VERSION 5.8 ;
BUSBITCHARS "[]" ;
DIVIDERCHAR "/" ;

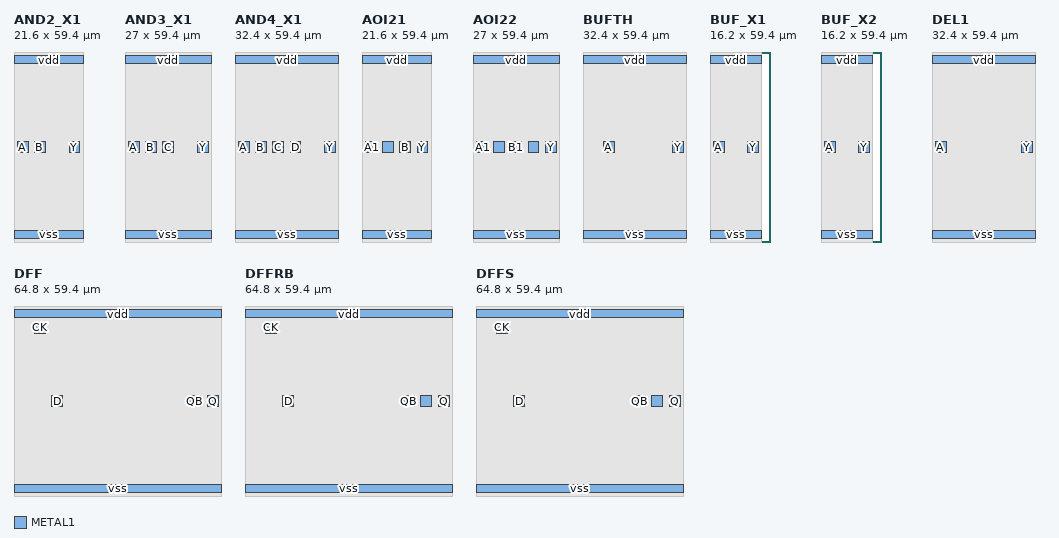
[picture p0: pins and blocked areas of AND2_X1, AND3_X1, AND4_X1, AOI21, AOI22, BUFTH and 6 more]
MACRO AND2_X1
  CLASS CORE ;
  FOREIGN AND2_X1 0.000 0.000 ;
  ORIGIN 0.000 0.000 ;
  SIZE 21.600 BY 59.400 ;
  SYMMETRY X Y ;
  SITE TR1UM ;
  PIN A
    DIRECTION INPUT ;
    USE SIGNAL ;
    PORT
      LAYER METAL1 ;
        RECT 1.000 28.000 4.400 31.400 ;
    END
  END A
  PIN B
    DIRECTION INPUT ;
    USE SIGNAL ;
    PORT
      LAYER METAL1 ;
        RECT 6.400 28.000 9.800 31.400 ;
    END
  END B
  PIN Y
    DIRECTION OUTPUT ;
    USE SIGNAL ;
    PORT
      LAYER METAL1 ;
        RECT 17.200 28.000 20.600 31.400 ;
    END
  END Y
  PIN vdd
    DIRECTION INOUT ;
    USE POWER ;
    SHAPE ABUTMENT ;
    PORT
      LAYER METAL1 ;
        RECT 0.000 55.700 21.600 58.300 ;
    END
  END vdd
  PIN vss
    DIRECTION INOUT ;
    USE GROUND ;
    SHAPE ABUTMENT ;
    PORT
      LAYER METAL1 ;
        RECT 0.000 1.100 21.600 3.700 ;
    END
  END vss
  OBS
    LAYER METAL1 ;
      RECT 0.000 0.000 21.600 59.400 ;
    LAYER VIA1 ;
      RECT 0.000 0.000 21.600 59.400 ;
  END
END AND2_X1

MACRO AND3_X1
  CLASS CORE ;
  FOREIGN AND3_X1 0.000 0.000 ;
  ORIGIN 0.000 0.000 ;
  SIZE 27.000 BY 59.400 ;
  SYMMETRY X Y ;
  SITE TR1UM ;
  PIN A
    DIRECTION INPUT ;
    USE SIGNAL ;
    PORT
      LAYER METAL1 ;
        RECT 1.000 28.000 4.400 31.400 ;
    END
  END A
  PIN B
    DIRECTION INPUT ;
    USE SIGNAL ;
    PORT
      LAYER METAL1 ;
        RECT 6.400 28.000 9.800 31.400 ;
    END
  END B
  PIN C
    DIRECTION INPUT ;
    USE SIGNAL ;
    PORT
      LAYER METAL1 ;
        RECT 11.800 28.000 15.200 31.400 ;
    END
  END C
  PIN Y
    DIRECTION OUTPUT ;
    USE SIGNAL ;
    PORT
      LAYER METAL1 ;
        RECT 22.600 28.000 26.000 31.400 ;
    END
  END Y
  PIN vdd
    DIRECTION INOUT ;
    USE POWER ;
    SHAPE ABUTMENT ;
    PORT
      LAYER METAL1 ;
        RECT 0.000 55.700 27.000 58.300 ;
    END
  END vdd
  PIN vss
    DIRECTION INOUT ;
    USE GROUND ;
    SHAPE ABUTMENT ;
    PORT
      LAYER METAL1 ;
        RECT 0.000 1.100 27.000 3.700 ;
    END
  END vss
  OBS
    LAYER METAL1 ;
      RECT 0.000 0.000 27.000 59.400 ;
    LAYER VIA1 ;
      RECT 0.000 0.000 27.000 59.400 ;
  END
END AND3_X1

MACRO AND4_X1
  CLASS CORE ;
  FOREIGN AND4_X1 0.000 0.000 ;
  ORIGIN 0.000 0.000 ;
  SIZE 32.400 BY 59.400 ;
  SYMMETRY X Y ;
  SITE TR1UM ;
  PIN A
    DIRECTION INPUT ;
    USE SIGNAL ;
    PORT
      LAYER METAL1 ;
        RECT 1.000 28.000 4.400 31.400 ;
    END
  END A
  PIN B
    DIRECTION INPUT ;
    USE SIGNAL ;
    PORT
      LAYER METAL1 ;
        RECT 6.400 28.000 9.800 31.400 ;
    END
  END B
  PIN C
    DIRECTION INPUT ;
    USE SIGNAL ;
    PORT
      LAYER METAL1 ;
        RECT 11.800 28.000 15.200 31.400 ;
    END
  END C
  PIN D
    DIRECTION INPUT ;
    USE SIGNAL ;
    PORT
      LAYER METAL1 ;
        RECT 17.200 28.000 20.600 31.400 ;
    END
  END D
  PIN Y
    DIRECTION OUTPUT ;
    USE SIGNAL ;
    PORT
      LAYER METAL1 ;
        RECT 28.000 28.000 31.400 31.400 ;
    END
  END Y
  PIN vdd
    DIRECTION INOUT ;
    USE POWER ;
    SHAPE ABUTMENT ;
    PORT
      LAYER METAL1 ;
        RECT 0.000 55.700 32.400 58.300 ;
    END
  END vdd
  PIN vss
    DIRECTION INOUT ;
    USE GROUND ;
    SHAPE ABUTMENT ;
    PORT
      LAYER METAL1 ;
        RECT 0.000 1.100 32.400 3.700 ;
    END
  END vss
  OBS
    LAYER METAL1 ;
      RECT 0.000 0.000 32.400 59.400 ;
    LAYER VIA1 ;
      RECT 0.000 0.000 32.400 59.400 ;
  END
END AND4_X1

MACRO AOI21
  CLASS CORE ;
  FOREIGN AOI21 0.000 0.000 ;
  ORIGIN 0.000 0.000 ;
  SIZE 21.600 BY 59.400 ;
  SYMMETRY X Y ;
  SITE TR1UM ;
  PIN A1
    DIRECTION INPUT ;
    USE SIGNAL ;
    PORT
      LAYER METAL1 ;
        RECT 1.000 28.000 4.400 31.400 ;
    END
  END A1
  PIN A2
    DIRECTION INPUT ;
    USE SIGNAL ;
    PORT
      LAYER METAL1 ;
        RECT 6.400 28.000 9.800 31.400 ;
    END
  END A2
  PIN B
    DIRECTION INPUT ;
    USE SIGNAL ;
    PORT
      LAYER METAL1 ;
        RECT 11.800 28.000 15.200 31.400 ;
    END
  END B
  PIN Y
    DIRECTION OUTPUT ;
    USE SIGNAL ;
    PORT
      LAYER METAL1 ;
        RECT 17.200 28.000 20.600 31.400 ;
    END
  END Y
  PIN vdd
    DIRECTION INOUT ;
    USE POWER ;
    SHAPE ABUTMENT ;
    PORT
      LAYER METAL1 ;
        RECT 0.000 55.700 21.600 58.300 ;
    END
  END vdd
  PIN vss
    DIRECTION INOUT ;
    USE GROUND ;
    SHAPE ABUTMENT ;
    PORT
      LAYER METAL1 ;
        RECT 0.000 1.100 21.600 3.700 ;
    END
  END vss
  OBS
    LAYER METAL1 ;
      RECT 0.000 0.000 21.600 59.400 ;
    LAYER VIA1 ;
      RECT 0.000 0.000 21.600 59.400 ;
  END
END AOI21

MACRO AOI22
  CLASS CORE ;
  FOREIGN AOI22 0.000 0.000 ;
  ORIGIN 0.000 0.000 ;
  SIZE 27.000 BY 59.400 ;
  SYMMETRY X Y ;
  SITE TR1UM ;
  PIN A1
    DIRECTION INPUT ;
    USE SIGNAL ;
    PORT
      LAYER METAL1 ;
        RECT 1.000 28.000 4.400 31.400 ;
    END
  END A1
  PIN A2
    DIRECTION INPUT ;
    USE SIGNAL ;
    PORT
      LAYER METAL1 ;
        RECT 6.400 28.000 9.800 31.400 ;
    END
  END A2
  PIN B1
    DIRECTION INPUT ;
    USE SIGNAL ;
    PORT
      LAYER METAL1 ;
        RECT 11.800 28.000 15.200 31.400 ;
    END
  END B1
  PIN B2
    DIRECTION INPUT ;
    USE SIGNAL ;
    PORT
      LAYER METAL1 ;
        RECT 17.200 28.000 20.600 31.400 ;
    END
  END B2
  PIN Y
    DIRECTION OUTPUT ;
    USE SIGNAL ;
    PORT
      LAYER METAL1 ;
        RECT 22.600 28.000 26.000 31.400 ;
    END
  END Y
  PIN vdd
    DIRECTION INOUT ;
    USE POWER ;
    SHAPE ABUTMENT ;
    PORT
      LAYER METAL1 ;
        RECT 0.000 55.700 27.000 58.300 ;
    END
  END vdd
  PIN vss
    DIRECTION INOUT ;
    USE GROUND ;
    SHAPE ABUTMENT ;
    PORT
      LAYER METAL1 ;
        RECT 0.000 1.100 27.000 3.700 ;
    END
  END vss
  OBS
    LAYER METAL1 ;
      RECT 0.000 0.000 27.000 59.400 ;
    LAYER VIA1 ;
      RECT 0.000 0.000 27.000 59.400 ;
  END
END AOI22

MACRO BUFTH
  CLASS CORE ;
  FOREIGN BUFTH 0.000 0.000 ;
  ORIGIN 0.000 0.000 ;
  SIZE 32.400 BY 59.400 ;
  SYMMETRY X Y ;
  SITE TR1UM ;
  PIN A
    DIRECTION INPUT ;
    USE SIGNAL ;
    PORT
      LAYER METAL1 ;
        RECT 6.400 28.000 9.800 31.400 ;
    END
  END A
  PIN Y
    DIRECTION OUTPUT ;
    USE SIGNAL ;
    PORT
      LAYER METAL1 ;
        RECT 28.000 28.000 31.400 31.400 ;
    END
  END Y
  PIN vdd
    DIRECTION INOUT ;
    USE POWER ;
    SHAPE ABUTMENT ;
    PORT
      LAYER METAL1 ;
        RECT 0.000 55.700 32.400 58.300 ;
    END
  END vdd
  PIN vss
    DIRECTION INOUT ;
    USE GROUND ;
    SHAPE ABUTMENT ;
    PORT
      LAYER METAL1 ;
        RECT 0.000 1.100 32.400 3.700 ;
    END
  END vss
  OBS
    LAYER METAL1 ;
      RECT 0.000 0.000 32.400 59.400 ;
    LAYER VIA1 ;
      RECT 0.000 0.000 32.400 59.400 ;
  END
END BUFTH

MACRO BUF_X1
  CLASS CORE ;
  FOREIGN BUF_X1 0.000 0.000 ;
  ORIGIN 0.000 0.000 ;
  SIZE 16.200 BY 59.400 ;
  SYMMETRY X Y ;
  SITE TR1UM ;
  PIN A
    DIRECTION INPUT ;
    USE SIGNAL ;
    PORT
      LAYER METAL1 ;
        RECT 1.000 28.000 4.400 31.400 ;
    END
  END A
  PIN Y
    DIRECTION OUTPUT ;
    USE SIGNAL ;
    PORT
      LAYER METAL1 ;
        RECT 11.800 28.000 15.200 31.400 ;
    END
  END Y
  PIN vdd
    DIRECTION INOUT ;
    USE POWER ;
    SHAPE ABUTMENT ;
    PORT
      LAYER METAL1 ;
        RECT 0.000 55.700 16.200 58.300 ;
    END
  END vdd
  PIN vss
    DIRECTION INOUT ;
    USE GROUND ;
    SHAPE ABUTMENT ;
    PORT
      LAYER METAL1 ;
        RECT 0.000 1.100 16.200 3.700 ;
    END
  END vss
  OBS
    LAYER METAL1 ;
      RECT 0.000 0.000 16.200 59.400 ;
    LAYER VIA1 ;
      RECT 0.000 0.000 16.200 59.400 ;
  END
END BUF_X1

MACRO BUF_X2
  CLASS CORE ;
  FOREIGN BUF_X2 0.000 0.000 ;
  ORIGIN 0.000 0.000 ;
  SIZE 16.200 BY 59.400 ;
  SYMMETRY X Y ;
  SITE TR1UM ;
  PIN A
    DIRECTION INPUT ;
    USE SIGNAL ;
    PORT
      LAYER METAL1 ;
        RECT 1.000 28.000 4.400 31.400 ;
    END
  END A
  PIN Y
    DIRECTION OUTPUT ;
    USE SIGNAL ;
    PORT
      LAYER METAL1 ;
        RECT 11.800 28.000 15.200 31.400 ;
    END
  END Y
  PIN vdd
    DIRECTION INOUT ;
    USE POWER ;
    SHAPE ABUTMENT ;
    PORT
      LAYER METAL1 ;
        RECT 0.000 55.700 16.200 58.300 ;
    END
  END vdd
  PIN vss
    DIRECTION INOUT ;
    USE GROUND ;
    SHAPE ABUTMENT ;
    PORT
      LAYER METAL1 ;
        RECT 0.000 1.100 16.200 3.700 ;
    END
  END vss
  OBS
    LAYER METAL1 ;
      RECT 0.000 0.000 16.200 59.400 ;
    LAYER VIA1 ;
      RECT 0.000 0.000 16.200 59.400 ;
  END
END BUF_X2

MACRO DEL1
  CLASS CORE ;
  FOREIGN DEL1 0.000 0.000 ;
  ORIGIN 0.000 0.000 ;
  SIZE 32.400 BY 59.400 ;
  SYMMETRY X Y ;
  SITE TR1UM ;
  PIN A
    DIRECTION INPUT ;
    USE SIGNAL ;
    PORT
      LAYER METAL1 ;
        RECT 1.000 28.000 4.400 31.400 ;
    END
  END A
  PIN Y
    DIRECTION OUTPUT ;
    USE SIGNAL ;
    PORT
      LAYER METAL1 ;
        RECT 28.000 28.000 31.400 31.400 ;
    END
  END Y
  PIN vdd
    DIRECTION INOUT ;
    USE POWER ;
    SHAPE ABUTMENT ;
    PORT
      LAYER METAL1 ;
        RECT 0.000 55.700 32.400 58.300 ;
    END
  END vdd
  PIN vss
    DIRECTION INOUT ;
    USE GROUND ;
    SHAPE ABUTMENT ;
    PORT
      LAYER METAL1 ;
        RECT 0.000 1.100 32.400 3.700 ;
    END
  END vss
  OBS
    LAYER METAL1 ;
      RECT 0.000 0.000 32.400 59.400 ;
    LAYER VIA1 ;
      RECT 0.000 0.000 32.400 59.400 ;
  END
END DEL1

MACRO DFF
  CLASS CORE ;
  FOREIGN DFF 0.000 0.000 ;
  ORIGIN 0.000 0.000 ;
  SIZE 64.800 BY 59.400 ;
  SYMMETRY X Y ;
  SITE TR1UM ;
  PIN CK
    DIRECTION INPUT ;
    USE SIGNAL ;
    PORT
      LAYER METAL1 ;
        RECT 6.400 50.900 9.800 54.300 ;
    END
  END CK
  PIN D
    DIRECTION INPUT ;
    USE SIGNAL ;
    PORT
      LAYER METAL1 ;
        RECT 11.800 27.900 15.200 31.300 ;
    END
  END D
  PIN Q
    DIRECTION OUTPUT ;
    USE SIGNAL ;
    PORT
      LAYER METAL1 ;
        RECT 60.400 27.900 63.800 31.300 ;
    END
  END Q
  PIN QB
    DIRECTION OUTPUT ;
    USE SIGNAL ;
    PORT
      LAYER METAL1 ;
        RECT 55.000 27.900 58.400 31.300 ;
    END
  END QB
  PIN vdd
    DIRECTION INOUT ;
    USE POWER ;
    SHAPE ABUTMENT ;
    PORT
      LAYER METAL1 ;
        RECT 0.000 55.700 64.800 58.300 ;
    END
  END vdd
  PIN vss
    DIRECTION INOUT ;
    USE GROUND ;
    SHAPE ABUTMENT ;
    PORT
      LAYER METAL1 ;
        RECT 0.000 1.100 64.800 3.700 ;
    END
  END vss
  OBS
    LAYER METAL1 ;
      RECT 0.000 0.000 64.800 59.400 ;
    LAYER VIA1 ;
      RECT 0.000 0.000 64.800 59.400 ;
  END
END DFF

MACRO DFFRB
  CLASS CORE ;
  FOREIGN DFFRB 0.000 0.000 ;
  ORIGIN 0.000 0.000 ;
  SIZE 64.800 BY 59.400 ;
  SYMMETRY X Y ;
  SITE TR1UM ;
  PIN CK
    DIRECTION INPUT ;
    USE SIGNAL ;
    PORT
      LAYER METAL1 ;
        RECT 6.400 50.900 9.800 54.300 ;
    END
  END CK
  PIN D
    DIRECTION INPUT ;
    USE SIGNAL ;
    PORT
      LAYER METAL1 ;
        RECT 11.800 27.900 15.200 31.300 ;
    END
  END D
  PIN Q
    DIRECTION OUTPUT ;
    USE SIGNAL ;
    PORT
      LAYER METAL1 ;
        RECT 60.400 27.900 63.800 31.300 ;
    END
  END Q
  PIN QB
    DIRECTION OUTPUT ;
    USE SIGNAL ;
    PORT
      LAYER METAL1 ;
        RECT 49.600 27.900 53.000 31.300 ;
        RECT 49.600 27.900 53.000 31.300 ;
    END
  END QB
  PIN RSTB
    DIRECTION INPUT ;
    USE SIGNAL ;
    PORT
      LAYER METAL1 ;
        RECT 55.000 27.900 58.400 31.300 ;
    END
  END RSTB
  PIN vdd
    DIRECTION INOUT ;
    USE POWER ;
    SHAPE ABUTMENT ;
    PORT
      LAYER METAL1 ;
        RECT 0.000 55.700 64.800 58.300 ;
    END
  END vdd
  PIN vss
    DIRECTION INOUT ;
    USE GROUND ;
    SHAPE ABUTMENT ;
    PORT
      LAYER METAL1 ;
        RECT 0.000 1.100 64.800 3.700 ;
    END
  END vss
  OBS
    LAYER METAL1 ;
      RECT 0.000 0.000 64.800 59.400 ;
    LAYER VIA1 ;
      RECT 0.000 0.000 64.800 59.400 ;
  END
END DFFRB

MACRO DFFS
  CLASS CORE ;
  FOREIGN DFFS 0.000 0.000 ;
  ORIGIN 0.000 0.000 ;
  SIZE 64.800 BY 59.400 ;
  SYMMETRY X Y ;
  SITE TR1UM ;
  PIN CK
    DIRECTION INPUT ;
    USE SIGNAL ;
    PORT
      LAYER METAL1 ;
        RECT 6.400 50.900 9.800 54.300 ;
    END
  END CK
  PIN D
    DIRECTION INPUT ;
    USE SIGNAL ;
    PORT
      LAYER METAL1 ;
        RECT 11.800 27.900 15.200 31.300 ;
    END
  END D
  PIN Q
    DIRECTION OUTPUT ;
    USE SIGNAL ;
    PORT
      LAYER METAL1 ;
        RECT 60.400 27.900 63.800 31.300 ;
    END
  END Q
  PIN QB
    DIRECTION OUTPUT ;
    USE SIGNAL ;
    PORT
      LAYER METAL1 ;
        RECT 49.600 27.900 53.000 31.300 ;
        RECT 49.600 27.900 53.000 31.300 ;
    END
  END QB
  PIN SET
    DIRECTION INPUT ;
    USE SIGNAL ;
    PORT
      LAYER METAL1 ;
        RECT 55.000 27.900 58.400 31.300 ;
    END
  END SET
  PIN vdd
    DIRECTION INOUT ;
    USE POWER ;
    SHAPE ABUTMENT ;
    PORT
      LAYER METAL1 ;
        RECT 0.000 55.700 64.800 58.300 ;
    END
  END vdd
  PIN vss
    DIRECTION INOUT ;
    USE GROUND ;
    SHAPE ABUTMENT ;
    PORT
      LAYER METAL1 ;
        RECT 0.000 1.100 64.800 3.700 ;
    END
  END vss
  OBS
    LAYER METAL1 ;
      RECT 0.000 0.000 64.800 59.400 ;
    LAYER VIA1 ;
      RECT 0.000 0.000 64.800 59.400 ;
  END
END DFFS

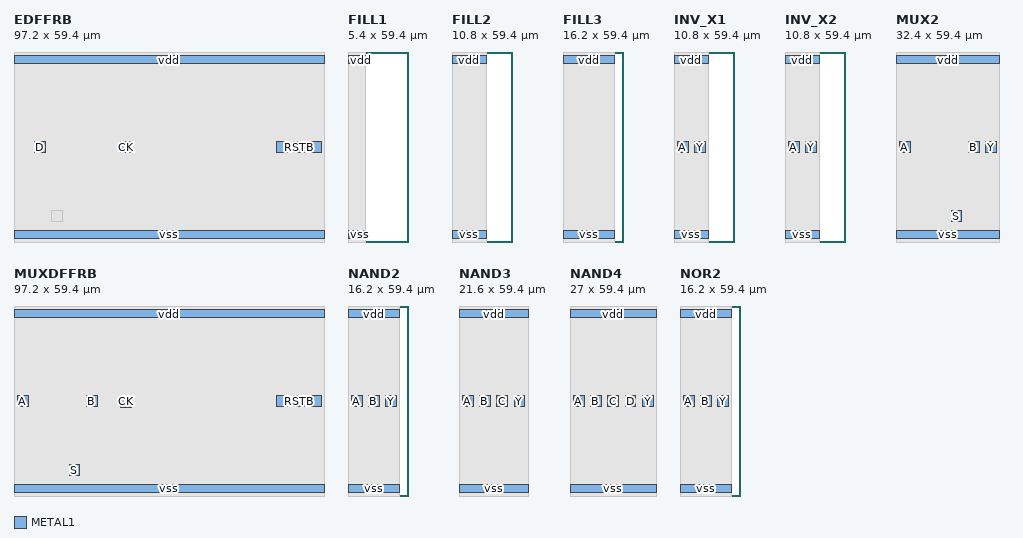
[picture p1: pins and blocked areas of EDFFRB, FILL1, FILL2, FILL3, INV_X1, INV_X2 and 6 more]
MACRO EDFFRB
  CLASS CORE ;
  FOREIGN EDFFRB 0.000 0.000 ;
  ORIGIN 0.000 0.000 ;
  SIZE 97.200 BY 59.400 ;
  SYMMETRY X Y ;
  SITE TR1UM ;
  PIN CK
    DIRECTION INPUT ;
    USE SIGNAL ;
    PORT
      LAYER METAL1 ;
        RECT 33.400 27.900 36.800 31.300 ;
    END
  END CK
  PIN D
    DIRECTION INPUT ;
    USE SIGNAL ;
    PORT
      LAYER METAL1 ;
        RECT 6.400 27.900 9.800 31.300 ;
    END
  END D
  PIN Q
    DIRECTION OUTPUT ;
    USE SIGNAL ;
    PORT
      LAYER METAL1 ;
        RECT 92.800 27.900 96.200 31.300 ;
    END
  END Q
  PIN QB
    DIRECTION OUTPUT ;
    USE SIGNAL ;
    PORT
      LAYER METAL1 ;
        RECT 82.000 27.900 85.400 31.300 ;
        RECT 82.000 27.900 85.400 31.300 ;
    END
  END QB
  PIN RSTB
    DIRECTION INPUT ;
    USE SIGNAL ;
    PORT
      LAYER METAL1 ;
        RECT 87.400 27.900 90.800 31.300 ;
    END
  END RSTB
  PIN vdd
    DIRECTION INOUT ;
    USE POWER ;
    SHAPE ABUTMENT ;
    PORT
      LAYER METAL1 ;
        RECT 0.000 55.700 97.200 58.300 ;
    END
  END vdd
  PIN vss
    DIRECTION INOUT ;
    USE GROUND ;
    SHAPE ABUTMENT ;
    PORT
      LAYER METAL1 ;
        RECT 0.000 1.100 97.200 3.700 ;
    END
  END vss
  OBS
    LAYER METAL1 ;
      RECT 0.000 0.000 97.200 59.400 ;
    LAYER VIA1 ;
      RECT 0.000 0.000 97.200 59.400 ;
    LAYER METAL1 ;
      RECT 11.800 6.300 15.200 9.700 ;
  END
END EDFFRB

MACRO FILL1
  CLASS CORE SPACER ;
  FOREIGN FILL1 0.000 0.000 ;
  ORIGIN 0.000 0.000 ;
  SIZE 5.400 BY 59.400 ;
  SYMMETRY X Y ;
  SITE TR1UM ;
  PIN vdd
    DIRECTION INOUT ;
    USE POWER ;
    SHAPE ABUTMENT ;
    PORT
      LAYER METAL1 ;
        RECT 0.000 55.700 5.400 58.300 ;
    END
  END vdd
  PIN vss
    DIRECTION INOUT ;
    USE GROUND ;
    SHAPE ABUTMENT ;
    PORT
      LAYER METAL1 ;
        RECT 0.000 1.100 5.400 3.700 ;
    END
  END vss
  OBS
    LAYER METAL1 ;
      RECT 0.000 0.000 5.400 59.400 ;
    LAYER VIA1 ;
      RECT 0.000 0.000 5.400 59.400 ;
  END
END FILL1

MACRO FILL2
  CLASS CORE SPACER ;
  FOREIGN FILL2 0.000 0.000 ;
  ORIGIN 0.000 0.000 ;
  SIZE 10.800 BY 59.400 ;
  SYMMETRY X Y ;
  SITE TR1UM ;
  PIN vdd
    DIRECTION INOUT ;
    USE POWER ;
    SHAPE ABUTMENT ;
    PORT
      LAYER METAL1 ;
        RECT 0.000 55.700 10.800 58.300 ;
    END
  END vdd
  PIN vss
    DIRECTION INOUT ;
    USE GROUND ;
    SHAPE ABUTMENT ;
    PORT
      LAYER METAL1 ;
        RECT 0.000 1.100 10.800 3.700 ;
    END
  END vss
  OBS
    LAYER METAL1 ;
      RECT 0.000 0.000 10.800 59.400 ;
    LAYER VIA1 ;
      RECT 0.000 0.000 10.800 59.400 ;
  END
END FILL2

MACRO FILL3
  CLASS CORE SPACER ;
  FOREIGN FILL3 0.000 0.000 ;
  ORIGIN 0.000 0.000 ;
  SIZE 16.200 BY 59.400 ;
  SYMMETRY X Y ;
  SITE TR1UM ;
  PIN vdd
    DIRECTION INOUT ;
    USE POWER ;
    SHAPE ABUTMENT ;
    PORT
      LAYER METAL1 ;
        RECT 0.000 55.700 16.200 58.300 ;
    END
  END vdd
  PIN vss
    DIRECTION INOUT ;
    USE GROUND ;
    SHAPE ABUTMENT ;
    PORT
      LAYER METAL1 ;
        RECT 0.000 1.100 16.200 3.700 ;
    END
  END vss
  OBS
    LAYER METAL1 ;
      RECT 0.000 0.000 16.200 59.400 ;
    LAYER VIA1 ;
      RECT 0.000 0.000 16.200 59.400 ;
  END
END FILL3

MACRO INV_X1
  CLASS CORE ;
  FOREIGN INV_X1 0.000 0.000 ;
  ORIGIN 0.000 0.000 ;
  SIZE 10.800 BY 59.400 ;
  SYMMETRY X Y ;
  SITE TR1UM ;
  PIN A
    DIRECTION INPUT ;
    USE SIGNAL ;
    PORT
      LAYER METAL1 ;
        RECT 1.000 28.000 4.400 31.400 ;
    END
  END A
  PIN Y
    DIRECTION OUTPUT ;
    USE SIGNAL ;
    PORT
      LAYER METAL1 ;
        RECT 6.400 28.000 9.800 31.400 ;
    END
  END Y
  PIN vdd
    DIRECTION INOUT ;
    USE POWER ;
    SHAPE ABUTMENT ;
    PORT
      LAYER METAL1 ;
        RECT 0.000 55.700 10.800 58.300 ;
    END
  END vdd
  PIN vss
    DIRECTION INOUT ;
    USE GROUND ;
    SHAPE ABUTMENT ;
    PORT
      LAYER METAL1 ;
        RECT 0.000 1.100 10.800 3.700 ;
    END
  END vss
  OBS
    LAYER METAL1 ;
      RECT 0.000 0.000 10.800 59.400 ;
    LAYER VIA1 ;
      RECT 0.000 0.000 10.800 59.400 ;
  END
END INV_X1

MACRO INV_X2
  CLASS CORE ;
  FOREIGN INV_X2 0.000 0.000 ;
  ORIGIN 0.000 0.000 ;
  SIZE 10.800 BY 59.400 ;
  SYMMETRY X Y ;
  SITE TR1UM ;
  PIN A
    DIRECTION INPUT ;
    USE SIGNAL ;
    PORT
      LAYER METAL1 ;
        RECT 1.000 28.000 4.400 31.400 ;
    END
  END A
  PIN Y
    DIRECTION OUTPUT ;
    USE SIGNAL ;
    PORT
      LAYER METAL1 ;
        RECT 6.400 28.000 9.800 31.400 ;
    END
  END Y
  PIN vdd
    DIRECTION INOUT ;
    USE POWER ;
    SHAPE ABUTMENT ;
    PORT
      LAYER METAL1 ;
        RECT 0.000 55.700 10.800 58.300 ;
    END
  END vdd
  PIN vss
    DIRECTION INOUT ;
    USE GROUND ;
    SHAPE ABUTMENT ;
    PORT
      LAYER METAL1 ;
        RECT 0.000 1.100 10.800 3.700 ;
    END
  END vss
  OBS
    LAYER METAL1 ;
      RECT 0.000 0.000 10.800 59.400 ;
    LAYER VIA1 ;
      RECT 0.000 0.000 10.800 59.400 ;
  END
END INV_X2

MACRO MUX2
  CLASS CORE ;
  FOREIGN MUX2 0.000 0.000 ;
  ORIGIN 0.000 0.000 ;
  SIZE 32.400 BY 59.400 ;
  SYMMETRY X Y ;
  SITE TR1UM ;
  PIN A
    DIRECTION INPUT ;
    USE SIGNAL ;
    PORT
      LAYER METAL1 ;
        RECT 1.000 27.900 4.400 31.300 ;
    END
  END A
  PIN B
    DIRECTION INPUT ;
    USE SIGNAL ;
    PORT
      LAYER METAL1 ;
        RECT 22.600 27.900 26.000 31.300 ;
    END
  END B
  PIN S
    DIRECTION INPUT ;
    USE SIGNAL ;
    PORT
      LAYER METAL1 ;
        RECT 17.200 6.300 20.600 9.700 ;
    END
  END S
  PIN Y
    DIRECTION OUTPUT ;
    USE SIGNAL ;
    PORT
      LAYER METAL1 ;
        RECT 28.000 27.900 31.400 31.300 ;
    END
  END Y
  PIN vdd
    DIRECTION INOUT ;
    USE POWER ;
    SHAPE ABUTMENT ;
    PORT
      LAYER METAL1 ;
        RECT 0.000 55.700 32.400 58.300 ;
    END
  END vdd
  PIN vss
    DIRECTION INOUT ;
    USE GROUND ;
    SHAPE ABUTMENT ;
    PORT
      LAYER METAL1 ;
        RECT 0.000 1.100 32.400 3.700 ;
    END
  END vss
  OBS
    LAYER METAL1 ;
      RECT 0.000 0.000 32.400 59.400 ;
    LAYER VIA1 ;
      RECT 0.000 0.000 32.400 59.400 ;
  END
END MUX2

MACRO MUXDFFRB
  CLASS CORE ;
  FOREIGN MUXDFFRB 0.000 0.000 ;
  ORIGIN 0.000 0.000 ;
  SIZE 97.200 BY 59.400 ;
  SYMMETRY X Y ;
  SITE TR1UM ;
  PIN A
    DIRECTION INPUT ;
    USE SIGNAL ;
    PORT
      LAYER METAL1 ;
        RECT 1.000 27.900 4.400 31.300 ;
    END
  END A
  PIN B
    DIRECTION INPUT ;
    USE SIGNAL ;
    PORT
      LAYER METAL1 ;
        RECT 22.600 27.900 26.000 31.300 ;
    END
  END B
  PIN CK
    DIRECTION INPUT ;
    USE SIGNAL ;
    PORT
      LAYER METAL1 ;
        RECT 33.400 27.700 36.800 31.100 ;
    END
  END CK
  PIN Q
    DIRECTION OUTPUT ;
    USE SIGNAL ;
    PORT
      LAYER METAL1 ;
        RECT 92.800 27.900 96.200 31.300 ;
    END
  END Q
  PIN QB
    DIRECTION OUTPUT ;
    USE SIGNAL ;
    PORT
      LAYER METAL1 ;
        RECT 82.000 27.900 85.400 31.300 ;
        RECT 82.000 27.900 85.400 31.300 ;
    END
  END QB
  PIN RSTB
    DIRECTION INPUT ;
    USE SIGNAL ;
    PORT
      LAYER METAL1 ;
        RECT 87.400 27.900 90.800 31.300 ;
    END
  END RSTB
  PIN S
    DIRECTION INPUT ;
    USE SIGNAL ;
    PORT
      LAYER METAL1 ;
        RECT 17.200 6.300 20.600 9.700 ;
    END
  END S
  PIN vdd
    DIRECTION INOUT ;
    USE POWER ;
    SHAPE ABUTMENT ;
    PORT
      LAYER METAL1 ;
        RECT 0.000 55.700 97.200 58.300 ;
    END
  END vdd
  PIN vss
    DIRECTION INOUT ;
    USE GROUND ;
    SHAPE ABUTMENT ;
    PORT
      LAYER METAL1 ;
        RECT 0.000 1.100 97.200 3.700 ;
    END
  END vss
  OBS
    LAYER METAL1 ;
      RECT 0.000 0.000 97.200 59.400 ;
    LAYER VIA1 ;
      RECT 0.000 0.000 97.200 59.400 ;
  END
END MUXDFFRB

MACRO NAND2
  CLASS CORE ;
  FOREIGN NAND2 0.000 0.000 ;
  ORIGIN 0.000 0.000 ;
  SIZE 16.200 BY 59.400 ;
  SYMMETRY X Y ;
  SITE TR1UM ;
  PIN A
    DIRECTION INPUT ;
    USE SIGNAL ;
    PORT
      LAYER METAL1 ;
        RECT 1.000 28.000 4.400 31.400 ;
    END
  END A
  PIN B
    DIRECTION INPUT ;
    USE SIGNAL ;
    PORT
      LAYER METAL1 ;
        RECT 6.400 28.000 9.800 31.400 ;
    END
  END B
  PIN Y
    DIRECTION OUTPUT ;
    USE SIGNAL ;
    PORT
      LAYER METAL1 ;
        RECT 11.800 28.000 15.200 31.400 ;
    END
  END Y
  PIN vdd
    DIRECTION INOUT ;
    USE POWER ;
    SHAPE ABUTMENT ;
    PORT
      LAYER METAL1 ;
        RECT 0.000 55.700 16.200 58.300 ;
    END
  END vdd
  PIN vss
    DIRECTION INOUT ;
    USE GROUND ;
    SHAPE ABUTMENT ;
    PORT
      LAYER METAL1 ;
        RECT 0.000 1.100 16.200 3.700 ;
    END
  END vss
  OBS
    LAYER METAL1 ;
      RECT 0.000 0.000 16.200 59.400 ;
    LAYER VIA1 ;
      RECT 0.000 0.000 16.200 59.400 ;
  END
END NAND2

MACRO NAND3
  CLASS CORE ;
  FOREIGN NAND3 0.000 0.000 ;
  ORIGIN 0.000 0.000 ;
  SIZE 21.600 BY 59.400 ;
  SYMMETRY X Y ;
  SITE TR1UM ;
  PIN A
    DIRECTION INPUT ;
    USE SIGNAL ;
    PORT
      LAYER METAL1 ;
        RECT 1.000 28.000 4.400 31.400 ;
    END
  END A
  PIN B
    DIRECTION INPUT ;
    USE SIGNAL ;
    PORT
      LAYER METAL1 ;
        RECT 6.400 28.000 9.800 31.400 ;
    END
  END B
  PIN C
    DIRECTION INPUT ;
    USE SIGNAL ;
    PORT
      LAYER METAL1 ;
        RECT 11.800 28.000 15.200 31.400 ;
    END
  END C
  PIN Y
    DIRECTION OUTPUT ;
    USE SIGNAL ;
    PORT
      LAYER METAL1 ;
        RECT 17.200 28.000 20.600 31.400 ;
    END
  END Y
  PIN vdd
    DIRECTION INOUT ;
    USE POWER ;
    SHAPE ABUTMENT ;
    PORT
      LAYER METAL1 ;
        RECT 0.000 55.700 21.600 58.300 ;
    END
  END vdd
  PIN vss
    DIRECTION INOUT ;
    USE GROUND ;
    SHAPE ABUTMENT ;
    PORT
      LAYER METAL1 ;
        RECT 0.000 1.100 21.600 3.700 ;
    END
  END vss
  OBS
    LAYER METAL1 ;
      RECT 0.000 0.000 21.600 59.400 ;
    LAYER VIA1 ;
      RECT 0.000 0.000 21.600 59.400 ;
  END
END NAND3

MACRO NAND4
  CLASS CORE ;
  FOREIGN NAND4 0.000 0.000 ;
  ORIGIN 0.000 0.000 ;
  SIZE 27.000 BY 59.400 ;
  SYMMETRY X Y ;
  SITE TR1UM ;
  PIN A
    DIRECTION INPUT ;
    USE SIGNAL ;
    PORT
      LAYER METAL1 ;
        RECT 1.000 28.000 4.400 31.400 ;
    END
  END A
  PIN B
    DIRECTION INPUT ;
    USE SIGNAL ;
    PORT
      LAYER METAL1 ;
        RECT 6.400 28.000 9.800 31.400 ;
    END
  END B
  PIN C
    DIRECTION INPUT ;
    USE SIGNAL ;
    PORT
      LAYER METAL1 ;
        RECT 11.800 28.000 15.200 31.400 ;
    END
  END C
  PIN D
    DIRECTION INPUT ;
    USE SIGNAL ;
    PORT
      LAYER METAL1 ;
        RECT 17.200 28.000 20.600 31.400 ;
    END
  END D
  PIN Y
    DIRECTION OUTPUT ;
    USE SIGNAL ;
    PORT
      LAYER METAL1 ;
        RECT 22.600 28.000 26.000 31.400 ;
    END
  END Y
  PIN vdd
    DIRECTION INOUT ;
    USE POWER ;
    SHAPE ABUTMENT ;
    PORT
      LAYER METAL1 ;
        RECT 0.000 55.700 27.000 58.300 ;
    END
  END vdd
  PIN vss
    DIRECTION INOUT ;
    USE GROUND ;
    SHAPE ABUTMENT ;
    PORT
      LAYER METAL1 ;
        RECT 0.000 1.100 27.000 3.700 ;
    END
  END vss
  OBS
    LAYER METAL1 ;
      RECT 0.000 0.000 27.000 59.400 ;
    LAYER VIA1 ;
      RECT 0.000 0.000 27.000 59.400 ;
  END
END NAND4

MACRO NOR2
  CLASS CORE ;
  FOREIGN NOR2 0.000 0.000 ;
  ORIGIN 0.000 0.000 ;
  SIZE 16.200 BY 59.400 ;
  SYMMETRY X Y ;
  SITE TR1UM ;
  PIN A
    DIRECTION INPUT ;
    USE SIGNAL ;
    PORT
      LAYER METAL1 ;
        RECT 1.000 28.000 4.400 31.400 ;
    END
  END A
  PIN B
    DIRECTION INPUT ;
    USE SIGNAL ;
    PORT
      LAYER METAL1 ;
        RECT 6.400 28.000 9.800 31.400 ;
    END
  END B
  PIN Y
    DIRECTION OUTPUT ;
    USE SIGNAL ;
    PORT
      LAYER METAL1 ;
        RECT 11.800 28.000 15.200 31.400 ;
    END
  END Y
  PIN vdd
    DIRECTION INOUT ;
    USE POWER ;
    SHAPE ABUTMENT ;
    PORT
      LAYER METAL1 ;
        RECT 0.000 55.700 16.200 58.300 ;
    END
  END vdd
  PIN vss
    DIRECTION INOUT ;
    USE GROUND ;
    SHAPE ABUTMENT ;
    PORT
      LAYER METAL1 ;
        RECT 0.000 1.100 16.200 3.700 ;
    END
  END vss
  OBS
    LAYER METAL1 ;
      RECT 0.000 0.000 16.200 59.400 ;
    LAYER VIA1 ;
      RECT 0.000 0.000 16.200 59.400 ;
  END
END NOR2

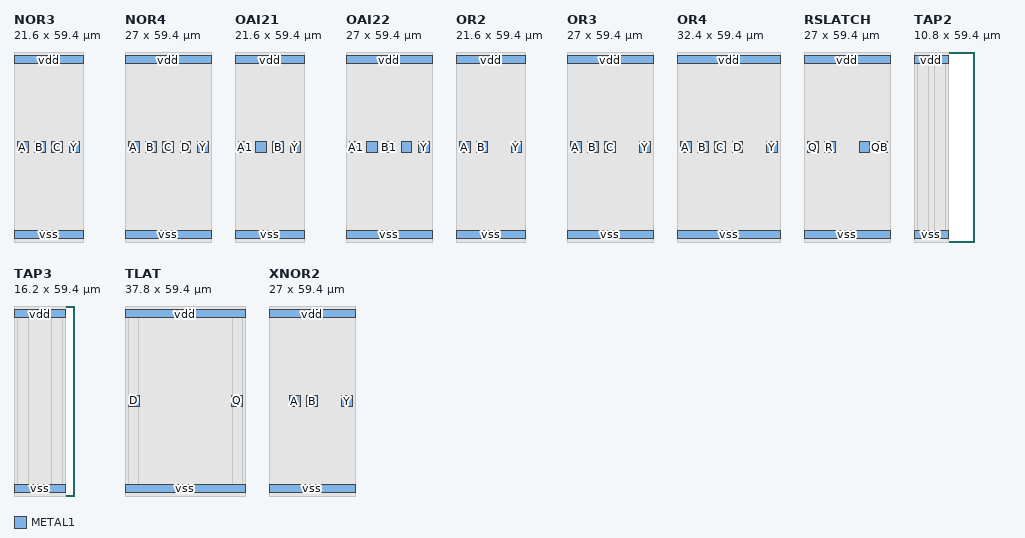
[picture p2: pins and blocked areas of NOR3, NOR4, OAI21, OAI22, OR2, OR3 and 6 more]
MACRO NOR3
  CLASS CORE ;
  FOREIGN NOR3 0.000 0.000 ;
  ORIGIN 0.000 0.000 ;
  SIZE 21.600 BY 59.400 ;
  SYMMETRY X Y ;
  SITE TR1UM ;
  PIN A
    DIRECTION INPUT ;
    USE SIGNAL ;
    PORT
      LAYER METAL1 ;
        RECT 1.000 28.000 4.400 31.400 ;
    END
  END A
  PIN B
    DIRECTION INPUT ;
    USE SIGNAL ;
    PORT
      LAYER METAL1 ;
        RECT 6.400 28.000 9.800 31.400 ;
    END
  END B
  PIN C
    DIRECTION INPUT ;
    USE SIGNAL ;
    PORT
      LAYER METAL1 ;
        RECT 11.800 28.000 15.200 31.400 ;
    END
  END C
  PIN Y
    DIRECTION OUTPUT ;
    USE SIGNAL ;
    PORT
      LAYER METAL1 ;
        RECT 17.200 28.000 20.600 31.400 ;
    END
  END Y
  PIN vdd
    DIRECTION INOUT ;
    USE POWER ;
    SHAPE ABUTMENT ;
    PORT
      LAYER METAL1 ;
        RECT 0.000 55.700 21.600 58.300 ;
    END
  END vdd
  PIN vss
    DIRECTION INOUT ;
    USE GROUND ;
    SHAPE ABUTMENT ;
    PORT
      LAYER METAL1 ;
        RECT 0.000 1.100 21.600 3.700 ;
    END
  END vss
  OBS
    LAYER METAL1 ;
      RECT 0.000 0.000 21.600 59.400 ;
    LAYER VIA1 ;
      RECT 0.000 0.000 21.600 59.400 ;
  END
END NOR3

MACRO NOR4
  CLASS CORE ;
  FOREIGN NOR4 0.000 0.000 ;
  ORIGIN 0.000 0.000 ;
  SIZE 27.000 BY 59.400 ;
  SYMMETRY X Y ;
  SITE TR1UM ;
  PIN A
    DIRECTION INPUT ;
    USE SIGNAL ;
    PORT
      LAYER METAL1 ;
        RECT 1.000 28.000 4.400 31.400 ;
    END
  END A
  PIN B
    DIRECTION INPUT ;
    USE SIGNAL ;
    PORT
      LAYER METAL1 ;
        RECT 6.400 28.000 9.800 31.400 ;
    END
  END B
  PIN C
    DIRECTION INPUT ;
    USE SIGNAL ;
    PORT
      LAYER METAL1 ;
        RECT 11.800 28.000 15.200 31.400 ;
    END
  END C
  PIN D
    DIRECTION INPUT ;
    USE SIGNAL ;
    PORT
      LAYER METAL1 ;
        RECT 17.200 28.000 20.600 31.400 ;
    END
  END D
  PIN Y
    DIRECTION OUTPUT ;
    USE SIGNAL ;
    PORT
      LAYER METAL1 ;
        RECT 22.600 28.000 26.000 31.400 ;
    END
  END Y
  PIN vdd
    DIRECTION INOUT ;
    USE POWER ;
    SHAPE ABUTMENT ;
    PORT
      LAYER METAL1 ;
        RECT 0.000 55.700 27.000 58.300 ;
    END
  END vdd
  PIN vss
    DIRECTION INOUT ;
    USE GROUND ;
    SHAPE ABUTMENT ;
    PORT
      LAYER METAL1 ;
        RECT 0.000 1.100 27.000 3.700 ;
    END
  END vss
  OBS
    LAYER METAL1 ;
      RECT 0.000 0.000 27.000 59.400 ;
    LAYER VIA1 ;
      RECT 0.000 0.000 27.000 59.400 ;
  END
END NOR4

MACRO OAI21
  CLASS CORE ;
  FOREIGN OAI21 0.000 0.000 ;
  ORIGIN 0.000 0.000 ;
  SIZE 21.600 BY 59.400 ;
  SYMMETRY X Y ;
  SITE TR1UM ;
  PIN A1
    DIRECTION INPUT ;
    USE SIGNAL ;
    PORT
      LAYER METAL1 ;
        RECT 1.000 28.000 4.400 31.400 ;
    END
  END A1
  PIN A2
    DIRECTION INPUT ;
    USE SIGNAL ;
    PORT
      LAYER METAL1 ;
        RECT 6.400 28.000 9.800 31.400 ;
    END
  END A2
  PIN B
    DIRECTION INPUT ;
    USE SIGNAL ;
    PORT
      LAYER METAL1 ;
        RECT 11.800 28.000 15.200 31.400 ;
    END
  END B
  PIN Y
    DIRECTION OUTPUT ;
    USE SIGNAL ;
    PORT
      LAYER METAL1 ;
        RECT 17.200 28.000 20.600 31.400 ;
    END
  END Y
  PIN vdd
    DIRECTION INOUT ;
    USE POWER ;
    SHAPE ABUTMENT ;
    PORT
      LAYER METAL1 ;
        RECT 0.000 55.700 21.600 58.300 ;
    END
  END vdd
  PIN vss
    DIRECTION INOUT ;
    USE GROUND ;
    SHAPE ABUTMENT ;
    PORT
      LAYER METAL1 ;
        RECT 0.000 1.100 21.600 3.700 ;
    END
  END vss
  OBS
    LAYER METAL1 ;
      RECT 0.000 0.000 21.600 59.400 ;
    LAYER VIA1 ;
      RECT 0.000 0.000 21.600 59.400 ;
  END
END OAI21

MACRO OAI22
  CLASS CORE ;
  FOREIGN OAI22 0.000 0.000 ;
  ORIGIN 0.000 0.000 ;
  SIZE 27.000 BY 59.400 ;
  SYMMETRY X Y ;
  SITE TR1UM ;
  PIN A1
    DIRECTION INPUT ;
    USE SIGNAL ;
    PORT
      LAYER METAL1 ;
        RECT 1.000 28.000 4.400 31.400 ;
    END
  END A1
  PIN A2
    DIRECTION INPUT ;
    USE SIGNAL ;
    PORT
      LAYER METAL1 ;
        RECT 6.400 28.000 9.800 31.400 ;
    END
  END A2
  PIN B1
    DIRECTION INPUT ;
    USE SIGNAL ;
    PORT
      LAYER METAL1 ;
        RECT 11.800 28.000 15.200 31.400 ;
    END
  END B1
  PIN B2
    DIRECTION INPUT ;
    USE SIGNAL ;
    PORT
      LAYER METAL1 ;
        RECT 17.200 28.000 20.600 31.400 ;
    END
  END B2
  PIN Y
    DIRECTION OUTPUT ;
    USE SIGNAL ;
    PORT
      LAYER METAL1 ;
        RECT 22.600 28.000 26.000 31.400 ;
    END
  END Y
  PIN vdd
    DIRECTION INOUT ;
    USE POWER ;
    SHAPE ABUTMENT ;
    PORT
      LAYER METAL1 ;
        RECT 0.000 55.700 27.000 58.300 ;
    END
  END vdd
  PIN vss
    DIRECTION INOUT ;
    USE GROUND ;
    SHAPE ABUTMENT ;
    PORT
      LAYER METAL1 ;
        RECT 0.000 1.100 27.000 3.700 ;
    END
  END vss
  OBS
    LAYER METAL1 ;
      RECT 0.000 0.000 27.000 59.400 ;
    LAYER VIA1 ;
      RECT 0.000 0.000 27.000 59.400 ;
  END
END OAI22

MACRO OR2
  CLASS CORE ;
  FOREIGN OR2 0.000 0.000 ;
  ORIGIN 0.000 0.000 ;
  SIZE 21.600 BY 59.400 ;
  SYMMETRY X Y ;
  SITE TR1UM ;
  PIN A
    DIRECTION INPUT ;
    USE SIGNAL ;
    PORT
      LAYER METAL1 ;
        RECT 1.000 28.000 4.400 31.400 ;
    END
  END A
  PIN B
    DIRECTION INPUT ;
    USE SIGNAL ;
    PORT
      LAYER METAL1 ;
        RECT 6.400 28.000 9.800 31.400 ;
    END
  END B
  PIN Y
    DIRECTION OUTPUT ;
    USE SIGNAL ;
    PORT
      LAYER METAL1 ;
        RECT 17.200 28.000 20.600 31.400 ;
        RECT 17.200 28.000 20.600 31.400 ;
    END
  END Y
  PIN vdd
    DIRECTION INOUT ;
    USE POWER ;
    SHAPE ABUTMENT ;
    PORT
      LAYER METAL1 ;
        RECT 0.000 55.700 21.600 58.300 ;
    END
  END vdd
  PIN vss
    DIRECTION INOUT ;
    USE GROUND ;
    SHAPE ABUTMENT ;
    PORT
      LAYER METAL1 ;
        RECT 0.000 1.100 21.600 3.700 ;
    END
  END vss
  OBS
    LAYER METAL1 ;
      RECT 0.000 0.000 21.600 59.400 ;
    LAYER VIA1 ;
      RECT 0.000 0.000 21.600 59.400 ;
  END
END OR2

MACRO OR3
  CLASS CORE ;
  FOREIGN OR3 0.000 0.000 ;
  ORIGIN 0.000 0.000 ;
  SIZE 27.000 BY 59.400 ;
  SYMMETRY X Y ;
  SITE TR1UM ;
  PIN A
    DIRECTION INPUT ;
    USE SIGNAL ;
    PORT
      LAYER METAL1 ;
        RECT 1.000 28.000 4.400 31.400 ;
    END
  END A
  PIN B
    DIRECTION INPUT ;
    USE SIGNAL ;
    PORT
      LAYER METAL1 ;
        RECT 6.400 28.000 9.800 31.400 ;
    END
  END B
  PIN C
    DIRECTION INPUT ;
    USE SIGNAL ;
    PORT
      LAYER METAL1 ;
        RECT 11.800 28.000 15.200 31.400 ;
    END
  END C
  PIN Y
    DIRECTION OUTPUT ;
    USE SIGNAL ;
    PORT
      LAYER METAL1 ;
        RECT 22.600 28.000 26.000 31.400 ;
    END
  END Y
  PIN vdd
    DIRECTION INOUT ;
    USE POWER ;
    SHAPE ABUTMENT ;
    PORT
      LAYER METAL1 ;
        RECT 0.000 55.700 27.000 58.300 ;
    END
  END vdd
  PIN vss
    DIRECTION INOUT ;
    USE GROUND ;
    SHAPE ABUTMENT ;
    PORT
      LAYER METAL1 ;
        RECT 0.000 1.100 27.000 3.700 ;
    END
  END vss
  OBS
    LAYER METAL1 ;
      RECT 0.000 0.000 27.000 59.400 ;
    LAYER VIA1 ;
      RECT 0.000 0.000 27.000 59.400 ;
  END
END OR3

MACRO OR4
  CLASS CORE ;
  FOREIGN OR4 0.000 0.000 ;
  ORIGIN 0.000 0.000 ;
  SIZE 32.400 BY 59.400 ;
  SYMMETRY X Y ;
  SITE TR1UM ;
  PIN A
    DIRECTION INPUT ;
    USE SIGNAL ;
    PORT
      LAYER METAL1 ;
        RECT 1.000 28.000 4.400 31.400 ;
    END
  END A
  PIN B
    DIRECTION INPUT ;
    USE SIGNAL ;
    PORT
      LAYER METAL1 ;
        RECT 6.400 28.000 9.800 31.400 ;
    END
  END B
  PIN C
    DIRECTION INPUT ;
    USE SIGNAL ;
    PORT
      LAYER METAL1 ;
        RECT 11.800 28.000 15.200 31.400 ;
    END
  END C
  PIN D
    DIRECTION INPUT ;
    USE SIGNAL ;
    PORT
      LAYER METAL1 ;
        RECT 17.200 28.000 20.600 31.400 ;
    END
  END D
  PIN Y
    DIRECTION OUTPUT ;
    USE SIGNAL ;
    PORT
      LAYER METAL1 ;
        RECT 28.000 28.000 31.400 31.400 ;
    END
  END Y
  PIN vdd
    DIRECTION INOUT ;
    USE POWER ;
    SHAPE ABUTMENT ;
    PORT
      LAYER METAL1 ;
        RECT 0.000 55.700 32.400 58.300 ;
    END
  END vdd
  PIN vss
    DIRECTION INOUT ;
    USE GROUND ;
    SHAPE ABUTMENT ;
    PORT
      LAYER METAL1 ;
        RECT 0.000 1.100 32.400 3.700 ;
    END
  END vss
  OBS
    LAYER METAL1 ;
      RECT 0.000 0.000 32.400 59.400 ;
    LAYER VIA1 ;
      RECT 0.000 0.000 32.400 59.400 ;
  END
END OR4

MACRO RSLATCH
  CLASS CORE ;
  FOREIGN RSLATCH 0.000 0.000 ;
  ORIGIN 0.000 0.000 ;
  SIZE 27.000 BY 59.400 ;
  SYMMETRY X Y ;
  SITE TR1UM ;
  PIN Q
    DIRECTION OUTPUT ;
    USE SIGNAL ;
    PORT
      LAYER METAL1 ;
        RECT 1.000 28.000 4.400 31.400 ;
    END
  END Q
  PIN QB
    DIRECTION OUTPUT ;
    USE SIGNAL ;
    PORT
      LAYER METAL1 ;
        RECT 22.600 28.000 26.000 31.400 ;
    END
  END QB
  PIN R
    DIRECTION INPUT ;
    USE SIGNAL ;
    PORT
      LAYER METAL1 ;
        RECT 6.400 28.000 9.800 31.400 ;
    END
  END R
  PIN S
    DIRECTION INPUT ;
    USE SIGNAL ;
    PORT
      LAYER METAL1 ;
        RECT 17.200 28.000 20.600 31.400 ;
    END
  END S
  PIN vdd
    DIRECTION INOUT ;
    USE POWER ;
    SHAPE ABUTMENT ;
    PORT
      LAYER METAL1 ;
        RECT 0.000 55.700 27.000 58.300 ;
    END
  END vdd
  PIN vss
    DIRECTION INOUT ;
    USE GROUND ;
    SHAPE ABUTMENT ;
    PORT
      LAYER METAL1 ;
        RECT 0.000 1.100 27.000 3.700 ;
    END
  END vss
  OBS
    LAYER METAL1 ;
      RECT 0.000 0.000 27.000 59.400 ;
    LAYER VIA1 ;
      RECT 0.000 0.000 27.000 59.400 ;
  END
END RSLATCH

MACRO TAP2
  CLASS CORE WELLTAP ;
  FOREIGN TAP2 0.000 0.000 ;
  ORIGIN 0.000 0.000 ;
  SIZE 10.800 BY 59.400 ;
  SYMMETRY X Y ;
  SITE TR1UM ;
  PIN vdd
    DIRECTION INOUT ;
    USE POWER ;
    SHAPE ABUTMENT ;
    PORT
      LAYER METAL1 ;
        RECT 0.000 55.700 10.800 58.300 ;
    END
  END vdd
  PIN vss
    DIRECTION INOUT ;
    USE GROUND ;
    SHAPE ABUTMENT ;
    PORT
      LAYER METAL1 ;
        RECT 0.000 1.100 10.800 3.700 ;
    END
  END vss
  OBS
    LAYER METAL1 ;
      RECT 0.000 0.000 10.800 59.400 ;
    LAYER VIA1 ;
      RECT 0.000 0.000 10.800 59.400 ;
    LAYER METAL1 ;
      RECT 6.400 1.100 9.800 58.300 ;
      RECT 1.000 1.100 4.400 58.300 ;
  END
END TAP2

MACRO TAP3
  CLASS CORE WELLTAP ;
  FOREIGN TAP3 0.000 0.000 ;
  ORIGIN 0.000 0.000 ;
  SIZE 16.200 BY 59.400 ;
  SYMMETRY X Y ;
  SITE TR1UM ;
  PIN vdd
    DIRECTION INOUT ;
    USE POWER ;
    SHAPE ABUTMENT ;
    PORT
      LAYER METAL1 ;
        RECT 0.000 55.700 16.200 58.300 ;
    END
  END vdd
  PIN vss
    DIRECTION INOUT ;
    USE GROUND ;
    SHAPE ABUTMENT ;
    PORT
      LAYER METAL1 ;
        RECT 0.000 1.100 16.200 3.700 ;
    END
  END vss
  OBS
    LAYER METAL1 ;
      RECT 0.000 0.000 16.200 59.400 ;
    LAYER VIA1 ;
      RECT 0.000 0.000 16.200 59.400 ;
    LAYER METAL1 ;
      RECT 11.800 1.100 15.200 58.300 ;
      RECT 1.000 1.100 4.400 58.300 ;
  END
END TAP3

MACRO TLAT
  CLASS BLOCK ;
  FOREIGN TLAT 0.000 0.000 ;
  ORIGIN 0.000 0.000 ;
  SIZE 37.800 BY 59.400 ;
  SYMMETRY X Y ;
  SITE TR1UM ;
  PIN D
    DIRECTION INPUT ;
    USE SIGNAL ;
    PORT
      LAYER METAL1 ;
        RECT 1.000 28.100 4.400 31.500 ;
    END
  END D
  PIN Q
    DIRECTION OUTPUT ;
    USE SIGNAL ;
    PORT
      LAYER METAL1 ;
        RECT 33.400 28.100 36.800 31.500 ;
    END
  END Q
  PIN vdd
    DIRECTION INOUT ;
    USE POWER ;
    SHAPE ABUTMENT ;
    PORT
      LAYER METAL1 ;
        RECT 0.000 55.700 37.800 58.300 ;
    END
  END vdd
  PIN vss
    DIRECTION INOUT ;
    USE GROUND ;
    SHAPE ABUTMENT ;
    PORT
      LAYER METAL1 ;
        RECT 0.000 1.100 37.800 3.700 ;
    END
  END vss
  OBS
    LAYER METAL1 ;
      RECT 0.000 0.000 37.800 59.400 ;
    LAYER VIA1 ;
      RECT 0.000 0.000 37.800 59.400 ;
    LAYER METAL1 ;
      RECT 1.200 2.400 4.200 28.100 ;
      RECT 33.600 2.400 36.600 28.100 ;
      RECT 1.200 31.500 4.200 57.000 ;
      RECT 33.600 31.500 36.600 57.000 ;
  END
END TLAT

MACRO XNOR2
  CLASS CORE ;
  FOREIGN XNOR2 0.000 0.000 ;
  ORIGIN 0.000 0.000 ;
  SIZE 27.000 BY 59.400 ;
  SYMMETRY X Y ;
  SITE TR1UM ;
  PIN A
    DIRECTION INPUT ;
    USE SIGNAL ;
    PORT
      LAYER METAL1 ;
        RECT 6.400 27.900 9.800 31.300 ;
    END
  END A
  PIN B
    DIRECTION INPUT ;
    USE SIGNAL ;
    PORT
      LAYER METAL1 ;
        RECT 11.800 27.900 15.200 31.300 ;
    END
  END B
  PIN Y
    DIRECTION OUTPUT ;
    USE SIGNAL ;
    PORT
      LAYER METAL1 ;
        RECT 22.600 27.900 26.000 31.300 ;
    END
  END Y
  PIN vdd
    DIRECTION INOUT ;
    USE POWER ;
    SHAPE ABUTMENT ;
    PORT
      LAYER METAL1 ;
        RECT 0.000 55.700 27.000 58.300 ;
    END
  END vdd
  PIN vss
    DIRECTION INOUT ;
    USE GROUND ;
    SHAPE ABUTMENT ;
    PORT
      LAYER METAL1 ;
        RECT 0.000 1.100 27.000 3.700 ;
    END
  END vss
  OBS
    LAYER METAL1 ;
      RECT 0.000 0.000 27.000 59.400 ;
    LAYER VIA1 ;
      RECT 0.000 0.000 27.000 59.400 ;
  END
END XNOR2

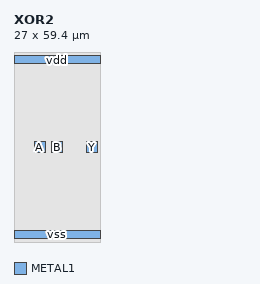
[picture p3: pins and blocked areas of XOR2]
MACRO XOR2
  CLASS CORE ;
  FOREIGN XOR2 0.000 0.000 ;
  ORIGIN 0.000 0.000 ;
  SIZE 27.000 BY 59.400 ;
  SYMMETRY X Y ;
  SITE TR1UM ;
  PIN A
    DIRECTION INPUT ;
    USE SIGNAL ;
    PORT
      LAYER METAL1 ;
        RECT 6.400 27.900 9.800 31.300 ;
    END
  END A
  PIN B
    DIRECTION INPUT ;
    USE SIGNAL ;
    PORT
      LAYER METAL1 ;
        RECT 11.800 27.900 15.200 31.300 ;
    END
  END B
  PIN Y
    DIRECTION OUTPUT ;
    USE SIGNAL ;
    PORT
      LAYER METAL1 ;
        RECT 22.600 27.900 26.000 31.300 ;
    END
  END Y
  PIN vdd
    DIRECTION INOUT ;
    USE POWER ;
    SHAPE ABUTMENT ;
    PORT
      LAYER METAL1 ;
        RECT 0.000 55.700 27.000 58.300 ;
    END
  END vdd
  PIN vss
    DIRECTION INOUT ;
    USE GROUND ;
    SHAPE ABUTMENT ;
    PORT
      LAYER METAL1 ;
        RECT 0.000 1.100 27.000 3.700 ;
    END
  END vss
  OBS
    LAYER METAL1 ;
      RECT 0.000 0.000 27.000 59.400 ;
    LAYER VIA1 ;
      RECT 0.000 0.000 27.000 59.400 ;
  END
END XOR2

END LIBRARY
